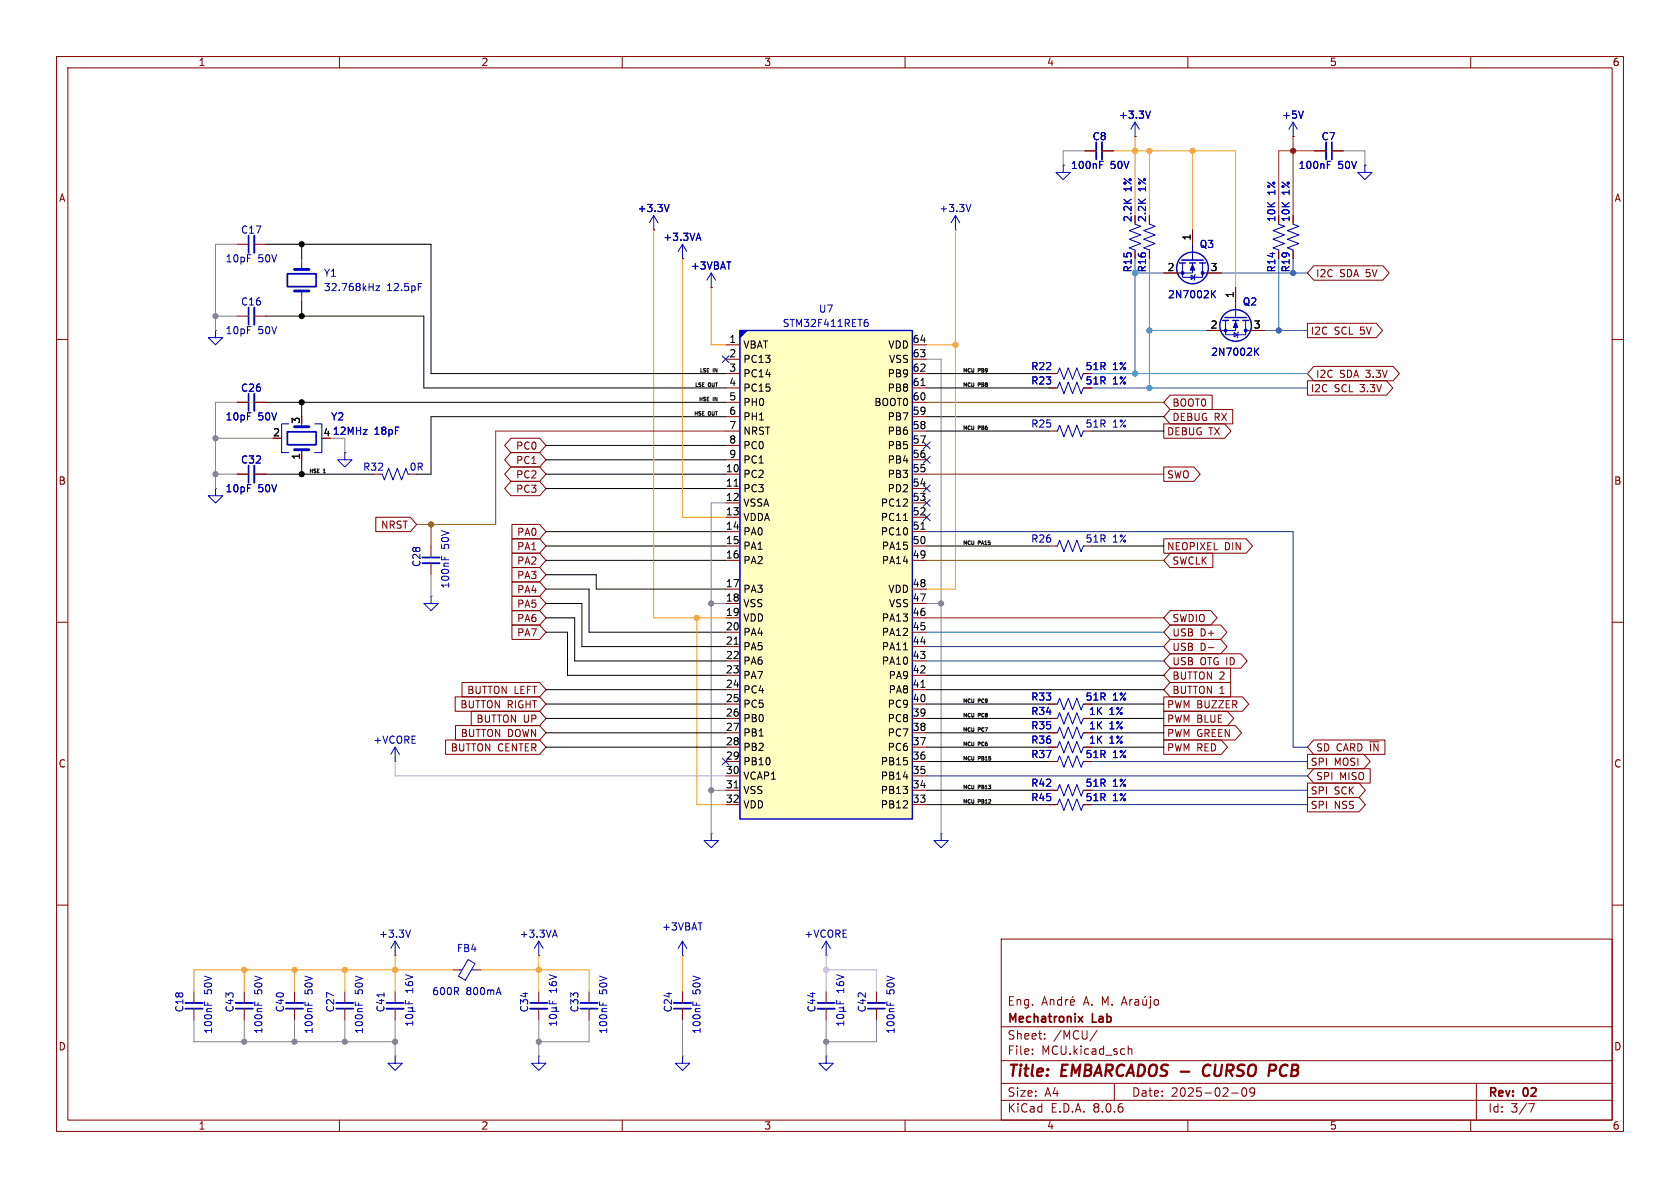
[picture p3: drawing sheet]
<svg xmlns="http://www.w3.org/2000/svg" width="297mm" height="210mm" viewBox="0 0 297 210" stroke-linecap="round" stroke-linejoin="round" font-family="sans-serif">
<defs><g id="words">
<g font-size="2.8" fill="#840000">
<text x="178" y="190.9">Title:</text>
<text x="187.7" y="190.9">EMBARCADOS -</text>
<text x="214.3" y="190.9">CURSO</text>
<text x="226.7" y="190.9">PCB</text>
</g>
<g font-size="2.1" fill="#840000">
<text x="178" y="178">Eng.</text>
<text x="191.6" y="178">A.</text>
<text x="178" y="184">Sheet:</text>
<text x="178" y="181.2">Mechatronix</text>
<text x="186.2" y="184">/MCU/</text>
<text x="193.2" y="181.2">Lab</text>
<text x="178" y="186.7">File:</text>
<text x="184.1" y="186.7">MCU.kicad_sch</text>
<text x="178" y="196.9">KiCad</text>
<text x="178" y="194.1">Size:</text>
<text x="184.7" y="194.1">A4</text>
<text x="185.7" y="196.9">E.D.A.</text>
<text x="193.3" y="196.9">8.0.6</text>
<text x="200" y="194.1">Date:</text>
<text x="207" y="194.1">2025-02-09</text>
<text x="263" y="194.3">Rev:</text>
<text x="263" y="196.9">Id:</text>
<text x="267.1" y="196.9">3/7</text>
<text x="269.4" y="194.3">02</text>
</g>
<g font-size="1.8" fill="#840000">
<text x="35" y="11.9">1</text>
<text x="85" y="11.9">2</text>
<text x="135" y="11.9">3</text>
<text x="185" y="11.9">4</text>
<text x="235" y="11.9">5</text>
<text x="285" y="11.9">6</text>
<text x="10.3" y="35.9">A</text>
<text x="285.3" y="35.9">A</text>
<text x="200.3" y="39.4" transform="rotate(-90 200.3 39.4)">2.2K</text>
<text x="202.8" y="39.4" transform="rotate(-90 202.8 39.4)">2.2K</text>
<text x="225.7" y="39.4" transform="rotate(-90 225.7 39.4)">10K</text>
<text x="228.2" y="39.4" transform="rotate(-90 228.2 39.4)">10K</text>
<text x="225.7" y="48.3" transform="rotate(-90 225.7 48.3)">R14</text>
<text x="232.6" y="49.2">I2C</text>
<text x="236.8" y="49.2">SDA 5V</text>
<text x="231.6" y="59.4">I2C</text>
<text x="235.9" y="59.4">SCL 5V</text>
<text x="191.8" y="65.6">51R</text>
<text x="191.8" y="68.2">51R</text>
<text x="231.6" y="69.5">I2C</text>
<text x="232.6" y="67">I2C</text>
<text x="235.9" y="69.5">SCL 3.3V</text>
<text x="236.8" y="67">SDA 3.3V</text>
<text x="206.2" y="77.2">DEBUG TX</text>
<text x="207.2" y="72.1">BOOT0</text>
<text x="207.2" y="74.6">DEBUG RX</text>
<text x="91.1" y="79.7">PC0</text>
<text x="91.1" y="82.2">PC1</text>
<text x="10.3" y="85.9">B</text>
<text x="91.1" y="84.8">PC2</text>
<text x="91.1" y="87.3">PC3</text>
<text x="206.2" y="84.8">SWO</text>
<text x="285.3" y="85.9">B</text>
<text x="67.3" y="93.7">NRST</text>
<text x="91.3" y="94.9">PA0</text>
<text x="91.3" y="100">PA2</text>
<text x="91.3" y="97.5">PA1</text>
<text x="206.2" y="97.5">NEOPIXEL</text>
<text x="207.2" y="100">SWCLK</text>
<text x="216.5" y="97.5">DIN</text>
<text x="91.3" y="107.6">PA5</text>
<text x="91.3" y="105.1">PA4</text>
<text x="91.3" y="102.6">PA3</text>
<text x="91.3" y="110.2">PA6</text>
<text x="91.3" y="112.7">PA7</text>
<text x="207.2" y="112.7">USB</text>
<text x="207.2" y="110.2">SWDIO</text>
<text x="212.1" y="112.7">D+</text>
<text x="207.2" y="115.3">USB</text>
<text x="207.2" y="117.8">USB</text>
<text x="212.1" y="115.3">D-</text>
<text x="212.1" y="117.8">OTG ID</text>
<text x="81.3" y="125.4">BUTTON RIGHT</text>
<text x="82.5" y="122.9">BUTTON LEFT</text>
<text x="191.8" y="124.1">51R</text>
<text x="206.2" y="125.4">PWM BUZZER</text>
<text x="207.2" y="122.9">BUTTON 1</text>
<text x="207.2" y="120.3">BUTTON 2</text>
<text x="81.3" y="130.5">BUTTON DOWN</text>
<text x="84.1" y="128">BUTTON UP</text>
<text x="206.2" y="130.5">PWM GREEN</text>
<text x="206.2" y="128">PWM BLUE</text>
<text x="10.3" y="135.9">C</text>
<text x="79.6" y="133">BUTTON CENTER</text>
<text x="191.8" y="134.2">51R</text>
<text x="206.2" y="133">PWM RED</text>
<text x="231.6" y="135.6">SPI</text>
<text x="232.6" y="133">SD CARD ~{IN}</text>
<text x="235.9" y="135.6">MOSI</text>
<text x="285.3" y="135.9">C</text>
<text x="191.8" y="139.3">51R</text>
<text x="191.8" y="141.8">51R</text>
<text x="231.6" y="140.7">SPI</text>
<text x="231.6" y="143.2">SPI</text>
<text x="232.6" y="138.1">SPI</text>
<text x="235.9" y="140.7">SCK</text>
<text x="235.9" y="143.2">NSS</text>
<text x="236.8" y="138.1">MISO</text>
<text x="10.3" y="185.9">D</text>
<text x="285.3" y="185.9">D</text>
<text x="35" y="199.9">1</text>
<text x="85" y="199.9">2</text>
<text x="135" y="199.9">3</text>
<text x="185" y="199.9">4</text>
<text x="235" y="199.9">5</text>
<text x="285" y="199.9">6</text>
</g>
<g font-size="1.8" fill="#0000c2">
<text x="197.7" y="21.2">+3.3V</text>
<text x="226.6" y="21.2">+5V</text>
<text x="193" y="25">C8</text>
<text x="233.5" y="25">C7</text>
<text x="189.2" y="30.1">100nF</text>
<text x="196.3" y="30.1">50V</text>
<text x="200.3" y="33.9" transform="rotate(-90 200.3 33.9)">1%</text>
<text x="202.8" y="33.9" transform="rotate(-90 202.8 33.9)">1%</text>
<text x="225.7" y="34.5" transform="rotate(-90 225.7 34.5)">1%</text>
<text x="228.2" y="34.5" transform="rotate(-90 228.2 34.5)">1%</text>
<text x="229.5" y="30.1">100nF</text>
<text x="236.5" y="30.1">50V</text>
<text x="42.5" y="41.5">C17</text>
<text x="112.6" y="37.7">+3.3V</text>
<text x="166" y="37.7">+3.3V</text>
<text x="39.8" y="46.6">10pF</text>
<text x="45.6" y="46.6">50V</text>
<text x="117.2" y="42.8">+3.3VA</text>
<text x="122" y="47.9">+3VBAT</text>
<text x="212" y="44">Q3</text>
<text x="57.2" y="49.1">Y1</text>
<text x="57.2" y="51.7">32.768kHz</text>
<text x="68.4" y="51.7">12.5pF</text>
<text x="200.3" y="48.3" transform="rotate(-90 200.3 48.3)">R15</text>
<text x="202.8" y="48.3" transform="rotate(-90 202.8 48.3)">R16</text>
<text x="206.4" y="52.9">2N7002K</text>
<text x="228.2" y="48.3" transform="rotate(-90 228.2 48.3)">R19</text>
<text x="39.8" y="59.3">10pF</text>
<text x="42.5" y="54.2">C16</text>
<text x="45.6" y="59.3">50V</text>
<text x="138.3" y="58">STM32F411RET6</text>
<text x="144.7" y="55.5">U7</text>
<text x="219.6" y="54.2">Q2</text>
<text x="182.2" y="65.6">R22</text>
<text x="196.7" y="65.6">1%</text>
<text x="214" y="63.1">2N7002K</text>
<text x="42.5" y="69.4">C26</text>
<text x="182.2" y="68.2">R23</text>
<text x="196.7" y="68.2">1%</text>
<text x="39.8" y="74.5">10pF</text>
<text x="45.6" y="74.5">50V</text>
<text x="58.4" y="74.5">Y2</text>
<text x="58.7" y="77.1">12MHz</text>
<text x="66.1" y="77.1">18pF</text>
<text x="182.2" y="75.8">R25</text>
<text x="191.8" y="75.8">51R</text>
<text x="196.7" y="75.8">1%</text>
<text x="42.5" y="82.1">C32</text>
<text x="64.1" y="83.4">R32</text>
<text x="72.3" y="83.4">0R</text>
<text x="39.8" y="87.2">10pF</text>
<text x="45.6" y="87.2">50V</text>
<text x="74.5" y="100.3" transform="rotate(-90 74.5 100.3)">C28</text>
<text x="79.6" y="97.1" transform="rotate(-90 79.6 97.1)">50V</text>
<text x="182.2" y="96.1">R26</text>
<text x="191.8" y="96.1">51R</text>
<text x="196.7" y="96.1">1%</text>
<text x="79.6" y="104.1" transform="rotate(-90 79.6 104.1)">100nF</text>
<text x="182.2" y="124.1">R33</text>
<text x="196.7" y="124.1">1%</text>
<text x="65.9" y="131.7">+VCORE</text>
<text x="182.2" y="131.7">R36</text>
<text x="182.2" y="129.1">R35</text>
<text x="182.2" y="126.6">R34</text>
<text x="192.4" y="131.7">1K</text>
<text x="192.4" y="129.1">1K</text>
<text x="192.4" y="126.6">1K</text>
<text x="196.1" y="131.7">1%</text>
<text x="196.1" y="129.1">1%</text>
<text x="196.1" y="126.6">1%</text>
<text x="182.2" y="134.2">R37</text>
<text x="196.7" y="134.2">1%</text>
<text x="182.2" y="139.3">R42</text>
<text x="182.2" y="141.8">R45</text>
<text x="196.7" y="139.3">1%</text>
<text x="196.7" y="141.8">1%</text>
<text x="66.9" y="166">+3.3V</text>
<text x="91.8" y="166">+3.3VA</text>
<text x="116.9" y="164.7">+3VBAT</text>
<text x="142.1" y="166">+VCORE</text>
<text x="80.7" y="168.5">FB4</text>
<text x="32.6" y="179.1" transform="rotate(-90 32.6 179.1)">C18</text>
<text x="37.7" y="175.8" transform="rotate(-90 37.7 175.8)">50V</text>
<text x="41.5" y="179.1" transform="rotate(-90 41.5 179.1)">C43</text>
<text x="46.6" y="175.8" transform="rotate(-90 46.6 175.8)">50V</text>
<text x="50.4" y="179.1" transform="rotate(-90 50.4 179.1)">C40</text>
<text x="55.5" y="175.8" transform="rotate(-90 55.5 175.8)">50V</text>
<text x="59.3" y="179.1" transform="rotate(-90 59.3 179.1)">C27</text>
<text x="64.4" y="175.8" transform="rotate(-90 64.4 175.8)">50V</text>
<text x="68.2" y="179.1" transform="rotate(-90 68.2 179.1)">C41</text>
<text x="73.3" y="175.6" transform="rotate(-90 73.3 175.6)">16V</text>
<text x="76.3" y="176.1">600R</text>
<text x="82.4" y="176.1">800mA</text>
<text x="93.6" y="179.1" transform="rotate(-90 93.6 179.1)">C34</text>
<text x="98.7" y="175.6" transform="rotate(-90 98.7 175.6)">16V</text>
<text x="102.5" y="179.1" transform="rotate(-90 102.5 179.1)">C33</text>
<text x="107.5" y="175.8" transform="rotate(-90 107.5 175.8)">50V</text>
<text x="119" y="179.1" transform="rotate(-90 119 179.1)">C24</text>
<text x="124.1" y="175.8" transform="rotate(-90 124.1 175.8)">50V</text>
<text x="144.4" y="179.1" transform="rotate(-90 144.4 179.1)">C44</text>
<text x="149.5" y="175.6" transform="rotate(-90 149.5 175.6)">16V</text>
<text x="153.3" y="179.1" transform="rotate(-90 153.3 179.1)">C42</text>
<text x="158.3" y="175.8" transform="rotate(-90 158.3 175.8)">50V</text>
<text x="37.7" y="182.9" transform="rotate(-90 37.7 182.9)">100nF</text>
<text x="46.6" y="182.9" transform="rotate(-90 46.6 182.9)">100nF</text>
<text x="55.5" y="182.9" transform="rotate(-90 55.5 182.9)">100nF</text>
<text x="64.4" y="182.9" transform="rotate(-90 64.4 182.9)">100nF</text>
<text x="107.5" y="182.9" transform="rotate(-90 107.5 182.9)">100nF</text>
<text x="124.1" y="182.9" transform="rotate(-90 124.1 182.9)">100nF</text>
<text x="158.3" y="182.9" transform="rotate(-90 158.3 182.9)">100nF</text>
</g>
<g font-size="1.8">
<text x="210.6" y="42.6" transform="rotate(-90 210.6 42.6)">1</text>
<text x="206.3" y="48">2</text>
<text x="213.9" y="48">3</text>
<text x="218.2" y="52.8" transform="rotate(-90 218.2 52.8)">1</text>
<text x="213.9" y="58.2">2</text>
<text x="221.5" y="58.2">3</text>
<text x="128.8" y="60.7">1</text>
<text x="128.8" y="63.2">2</text>
<text x="128.8" y="65.8">3</text>
<text x="131.3" y="61.8">VBAT</text>
<text x="131.3" y="64.4">PC13</text>
<text x="157" y="61.8">VDD</text>
<text x="157.1" y="64.4">VSS</text>
<text x="161.2" y="65.8">62</text>
<text x="161.2" y="63.2">63</text>
<text x="161.2" y="60.7">64</text>
<text x="128.8" y="68.3">4</text>
<text x="128.8" y="70.9">5</text>
<text x="131.3" y="66.9">PC14</text>
<text x="131.3" y="69.4">PC15</text>
<text x="131.3" y="72">PH0</text>
<text x="154.5" y="72">BOOT0</text>
<text x="156.8" y="69.4">PB8</text>
<text x="156.8" y="66.9">PB9</text>
<text x="161.2" y="70.9">60</text>
<text x="161.2" y="68.3">61</text>
<text x="48.2" y="77.2">2</text>
<text x="53.1" y="75" transform="rotate(-90 53.1 75)">3</text>
<text x="57.1" y="77.2">4</text>
<text x="128.8" y="73.4">6</text>
<text x="128.8" y="75.9">7</text>
<text x="131.3" y="74.5">PH1</text>
<text x="131.3" y="77.1">NRST</text>
<text x="156.8" y="77.1">PB6</text>
<text x="156.8" y="74.5">PB7</text>
<text x="161.2" y="75.9">58</text>
<text x="161.2" y="73.4">59</text>
<text x="53.1" y="81.4" transform="rotate(-90 53.1 81.4)">1</text>
<text x="128.2" y="83.6">10</text>
<text x="128.8" y="78.5">8</text>
<text x="128.8" y="81">9</text>
<text x="131.3" y="79.6">PC0</text>
<text x="131.3" y="82.1">PC1</text>
<text x="156.8" y="82.1">PB4</text>
<text x="156.8" y="79.6">PB5</text>
<text x="161.2" y="83.6">55</text>
<text x="161.2" y="81">56</text>
<text x="161.2" y="78.5">57</text>
<text x="128.2" y="86.1">11</text>
<text x="128.2" y="88.6">12</text>
<text x="131.3" y="84.7">PC2</text>
<text x="131.3" y="87.2">PC3</text>
<text x="131.3" y="89.8">VSSA</text>
<text x="155.6" y="89.8">PC12</text>
<text x="156.8" y="87.2">PD2</text>
<text x="156.8" y="84.7">PB3</text>
<text x="161.2" y="88.6">53</text>
<text x="161.2" y="86.1">54</text>
<text x="128.2" y="91.2">13</text>
<text x="128.2" y="93.7">14</text>
<text x="131.3" y="92.3">VDDA</text>
<text x="131.3" y="94.8">PA0</text>
<text x="155.6" y="94.8">PC10</text>
<text x="155.6" y="92.3">PC11</text>
<text x="161.2" y="93.7">51</text>
<text x="161.2" y="91.2">52</text>
<text x="128.2" y="96.3">15</text>
<text x="128.2" y="98.8">16</text>
<text x="131.3" y="97.4">PA1</text>
<text x="131.3" y="99.9">PA2</text>
<text x="155.8" y="99.9">PA14</text>
<text x="155.8" y="97.4">PA15</text>
<text x="161.2" y="98.8">49</text>
<text x="161.2" y="96.3">50</text>
<text x="128.2" y="103.9">17</text>
<text x="128.2" y="106.4">18</text>
<text x="131.3" y="105">PA3</text>
<text x="131.3" y="107.5">VSS</text>
<text x="157" y="105">VDD</text>
<text x="157.1" y="107.5">VSS</text>
<text x="161.2" y="106.4">47</text>
<text x="161.2" y="103.9">48</text>
<text x="128.2" y="109">19</text>
<text x="128.2" y="111.5">20</text>
<text x="131.3" y="110.1">VDD</text>
<text x="131.3" y="112.6">PA4</text>
<text x="155.8" y="112.6">PA12</text>
<text x="155.8" y="110.1">PA13</text>
<text x="161.2" y="111.5">45</text>
<text x="161.2" y="109">46</text>
<text x="128.2" y="114">21</text>
<text x="128.2" y="116.6">22</text>
<text x="128.2" y="119.1">23</text>
<text x="131.3" y="115.2">PA5</text>
<text x="131.3" y="117.7">PA6</text>
<text x="155.8" y="117.7">PA10</text>
<text x="155.8" y="115.2">PA11</text>
<text x="161.2" y="119.1">42</text>
<text x="161.2" y="116.6">43</text>
<text x="161.2" y="114">44</text>
<text x="128.2" y="121.7">24</text>
<text x="128.2" y="124.2">25</text>
<text x="131.3" y="120.2">PA7</text>
<text x="131.3" y="122.8">PC4</text>
<text x="131.3" y="125.3">PC5</text>
<text x="156.8" y="125.3">PC9</text>
<text x="157" y="122.8">PA8</text>
<text x="157" y="120.2">PA9</text>
<text x="161.2" y="124.2">40</text>
<text x="161.2" y="121.7">41</text>
<text x="128.2" y="126.7">26</text>
<text x="128.2" y="129.3">27</text>
<text x="128.2" y="131.8">28</text>
<text x="131.3" y="127.9">PB0</text>
<text x="131.3" y="130.4">PB1</text>
<text x="156.8" y="130.4">PC7</text>
<text x="156.8" y="127.9">PC8</text>
<text x="161.2" y="131.8">37</text>
<text x="161.2" y="129.3">38</text>
<text x="161.2" y="126.7">39</text>
<text x="128.2" y="134.4">29</text>
<text x="128.2" y="136.9">30</text>
<text x="131.3" y="132.9">PB2</text>
<text x="131.3" y="135.5">PB10</text>
<text x="155.6" y="135.5">PB15</text>
<text x="156.8" y="132.9">PC6</text>
<text x="161.2" y="136.9">35</text>
<text x="161.2" y="134.4">36</text>
<text x="128.2" y="139.4">31</text>
<text x="128.2" y="142">32</text>
<text x="131.3" y="138">VCAP1</text>
<text x="131.3" y="140.6">VSS</text>
<text x="131.3" y="143.1">VDD</text>
<text x="155.6" y="143.1">PB12</text>
<text x="155.6" y="140.6">PB13</text>
<text x="155.6" y="138">PB14</text>
<text x="161.2" y="142">33</text>
<text x="161.2" y="139.4">34</text>
</g>
<g font-size=".9" fill="#0f0f0f">
<text x="123.5" y="65.9">LSE</text>
<text x="126" y="65.9">IN</text>
<text x="170.2" y="65.9">MCU</text>
<text x="173" y="65.9">PB9</text>
<text x="122.7" y="68.4">LSE</text>
<text x="123.4" y="70.9">HSE</text>
<text x="125.2" y="68.4">OUT</text>
<text x="126" y="70.9">IN</text>
<text x="170.2" y="68.4">MCU</text>
<text x="173" y="68.4">PB8</text>
<text x="122.5" y="73.5">HSE</text>
<text x="125.2" y="73.5">OUT</text>
<text x="170.2" y="76">MCU</text>
<text x="173" y="76">PB6</text>
<text x="54.6" y="83.6">HSE</text>
<text x="57.3" y="83.6">1</text>
<text x="170.2" y="96.3">MCU</text>
<text x="173" y="96.3">PA15</text>
<text x="170.2" y="124.3">MCU</text>
<text x="173" y="124.3">PC9</text>
<text x="170.2" y="131.9">MCU</text>
<text x="170.2" y="126.8">MCU</text>
<text x="170.2" y="129.4">MCU</text>
<text x="173" y="131.9">PC6</text>
<text x="173" y="126.8">PC8</text>
<text x="173" y="129.4">PC7</text>
<text x="170.2" y="134.4">MCU</text>
<text x="173" y="134.4">PB15</text>
<text x="170.2" y="139.5">MCU</text>
<text x="170.2" y="142.1">MCU</text>
<text x="173" y="139.5">PB13</text>
<text x="173" y="142.1">PB12</text>
</g>
</g></defs>
<g fill="none" stroke="#840000" stroke-width=".18">
<path d="M10 10h277v190h-277zM12 12h273v186h-273zM60 10v2M110 10v2M160 10v2M210 10v2M260 10v2M10 60h2M38.1 58.4h.1M125.7 50.8h.1M285 60h2M10 110h2"/>
<path d="M76.2 105.4h.1M285 110h2M185.4 132.1h1.3M191.8 132.1h1.2M10 160h2M285 160h2M52.1 175.3v2M52.1 178.3v2M61 175.3v2M61 178.3v2M177 166h108v32h-108zM184.2 177.7l.5-1.5 .5 1.5"/>
<path d="M184.3 177.3h.7M185.7 176.7v1M185.7 176.8l.2-.1 .3 .1 .1 .9M187.7 176.8l-.5-.1-.2 .3v.4l.1 .2h.6M187.7 176.2v1.5M188.4 176.7v1M188.8 176.7l-.3 .1-.1 .2M189.2 177.2l.8-.1-.1-.3-.4-.1-.3 .2 .1 .7h.6M189.7 176.1l-.2 .2M194.9 177.7v-1.5l.5 1.1 .5-1.1v1.5M196.6 177.6v.1M198.2 177.7l.5-1.5 .5 1.5"/>
<path d="M198.4 177.3h.7M199.7 176.7v1M200.2 176.7l-.3 .1-.2 .2M200.7 176.8h.5l.1 .9M201.3 177.1h-.5a.29 .29 0 0 0-.2 .3 .29 .29 0 0 0 .2 .3l.5-.1M202 176.7l.1 .9 .4 .1 .2-.1M202.5 176.1l-.2 .2M202.7 176.7v1M203.4 176.2v.1M203.4 176.7v1.3l-.3 .2M204.2 176.8l.3-.1 .3 .3v.4l-.3 .3-.3-.1-.2-.2v-.4zM60 198v2"/>
<path d="M110 198v2M160 198v2M177 194.5h108M177 191.5h108M177 187.5h108M177 181.5h108M182.5 186.3v.1M182.5 185.5v.1M184.7 183.6v.1M184.7 182.8v.1M194 182.1l-1.3 2M197 191.5v3"/>
<path d="M199.5 184.9v1.5M199.5 185.5l.2-.1 .3 .1 .1 .9M210 198v2M217.7 193.2h1.2M219.7 192.4l.2-.1a.81 .81 0 0 1 .6 .6 .81 .81 0 0 1-.3 .8l-.2 .1a.81 .81 0 0 1-.3-1.4zM221.8 192.9l-.3 .3h-.3l-.2-.3 .1-.5 .4-.1 .2 .1a.99 .99 0 0 1-.3 1.4h-.3M260 198v2M261 191.5v6.5M270.2 195.1h1l-.6 1.5"/>
</g>
<path d="M213.6 188.2a1.13 1.13 0 0 0-.9 .7 1.13 1.13 0 0 0 .2 1.2l.3 .1 .5-.1M225.4 188.3a.53 .53 0 0 1 0 .8" fill="none" stroke="#840000" stroke-width=".4"/>
<path d="M190.6 179.7l.8 1M191.4 179.7l-.8 1" fill="none" stroke="#840000" stroke-width=".3"/>
<path d="M38.1 58.4v1.3h1.3l-1.3 1.3-1.3-1.3h1.3M125.7 48.3l-.7 1.2M125.7 48.3v2.5M125.7 48.3l.8 1.2M76.2 105.4v1.3h1.3l-1.3 1.3-1.3-1.3h1.3M186.7 132.1h.2l.4-1 .8 2 .7-2 .8 2 .8-2 .7 2 .4-1h.3M53.9 177.1v.6M54.5 177.3v.4M62.8 177.1v.6M63.4 177.3v.4" fill="none" stroke="#0000c2" stroke-width=".18"/>
<path d="M50.5 177.3h3.1M59.4 177.3h3.1" fill="none" stroke="#0000c2" stroke-width=".33"/>
<path d="M50.5 178.3h3.1M59.4 178.3h3.1" fill="none" stroke="#0000c2" stroke-width=".3"/>
<path d="M130.8 58.4h30.5v86.4h-30.5z" fill="#ffffc2"/>
<g fill="none" stroke="#0000c2" stroke-width=".25">
<path d="M130.8 58.4h30.5v86.4h-30.5zM208.5 46.5h1M208.9 46h3.8M210.3 46.5h1M212.1 46.5h1M216.2 56.6h1M216.5 56.1h3.8M217.9 56.6h1M219.7 56.6h1"/>
<circle cx="210.8" cy="47.4" r="2.79"/>
<circle cx="218.4" cy="57.5" r="2.79"/>
</g>
<g fill="#0000c2" stroke="#0000c2" stroke-width=".18">
<path d="M130.8 58.4h1.3l-1.3 1.3z"/>
<path d="M218.4 56.9l.4 1h-.7z"/>
<path d="M210.8 46.7l.4 1.1h-.8z"/>
<circle cx="216.7" cy="58.4" r=".25"/>
<circle cx="220.2" cy="58.4" r=".25"/>
<circle cx="209" cy="48.3" r=".25"/>
<circle cx="212.6" cy="48.3" r=".25"/>
</g>
<g fill="none" stroke="#840000" stroke-width=".18">
<path d="M188 29.2h.1M191.8 26.7h2M194.8 26.7h2M200.7 24.1h.1M228.6 24.1h.1M232.4 26.7h2M235.5 26.7h2M241.3 29.2h.1M41.9 55.9h2M41.9 43.2h2M45 55.9h2M45 43.2h2"/>
<path d="M53.3 45.7v1.3M53.3 52.1v1.2M115.6 40.6h.1M120.6 45.7h.1M125.7 50.8h.1M168.9 40.6h.1M200.7 44.5v1.2M203.2 44.5v1.2M205.7 48.3h2.6M210.8 40.6v2.6M213.4 58.4h2.5M213.4 48.3h2.5"/>
<path d="M218.4 50.8v2.5M221 58.4h2.5M228.6 44.5v1.2M231.1 57.1h12.2l1.1 1.3-1.1 1.3h-12.2zM232.3 47h12.2l1.1 1.3-1.1 1.2h-12.2l-1.2-1.2zM41.9 71.1h2M45 71.1h2M90.3 77.5h5.1l1.1 1.2-1.1 1.3h-5.1l-1.1-1.3zM128.3 61h2.5M128.3 63.5h2.5M128.3 66h2.5M128.3 68.6h2.5"/>
<path d="M128.3 71.1h2.5M128.3 78.7h2.5M128.3 76.2h2.5M128.3 73.7h2.5M161.3 61h2.5M161.3 63.5h2.5M161.3 66h2.5M161.3 68.6h2.5M161.3 71.1h2.5M161.3 78.7h2.5M161.3 76.2h2.5M161.3 73.7h2.5"/>
<path d="M185.4 66h1.3M185.4 68.6h1.3M185.4 76.2h1.3M205.7 74.9h10.8l1.1 1.3-1.1 1.3h-10.8zM206.9 69.8h7.4v2.6h-7.4l-1.2-1.3zM206.9 72.4h11v2.5h-11l-1.2-1.2zM231.1 67.3h14l1.1 1.3-1.1 1.3h-14zM232.3 64.8h14l1.1 1.2-1.1 1.3h-14l-1.2-1.3zM38.1 86.4h.1M41.9 83.8h2M45 83.8h2M53.3 80v1.3"/>
<path d="M61 80h.1M66.4 91.4h6.1l1.2 1.3-1.2 1.3h-6.1zM76.2 96.5v2.1M76.2 99.6v2M90.3 80h5.1l1.1 1.3-1.1 1.3h-5.1l-1.1-1.3zM90.3 82.5h5.1l1.1 1.3-1.1 1.3h-5.1l-1.1-1.3zM90.3 85.1h5.1l1.1 1.3-1.1 1.2h-5.1l-1.1-1.2zM90.5 97.8h4.9l1.1 1.3-1.1 1.2h-4.9zM90.5 92.7h4.9l1.1 1.3-1.1 1.3h-4.9zM90.5 95.2h4.9l1.1 1.3-1.1 1.3h-4.9zM128.3 83.8h2.5M128.3 86.4h2.5"/>
<path d="M128.3 88.9h2.5M128.3 91.4h2.5M128.3 94h2.5M128.3 96.5h2.5M128.3 99.1h2.5M128.3 81.3h2.5M161.3 83.8h2.5M161.3 86.4h2.5M161.3 88.9h2.5M161.3 91.4h2.5M161.3 94h2.5M161.3 96.5h2.5"/>
<path d="M161.3 99.1h2.5M161.3 81.3h2.5M185.4 96.5h1.3M205.7 95.2h14.6l1.1 1.3-1.1 1.3h-14.6zM205.7 82.5h5.4l1.1 1.3-1.1 1.3h-5.4zM206.9 97.8h7.5v2.5h-7.5l-1.2-1.2zM90.5 105.4h4.9l1.1 1.3-1.1 1.3h-4.9zM90.5 107.9h4.9l1.1 1.3-1.1 1.3h-4.9zM90.5 110.5h4.9l1.1 1.3-1.1 1.2h-4.9zM90.5 102.9h4.9l1.1 1.2-1.1 1.3h-4.9zM90.5 100.3h4.9l1.1 1.3-1.1 1.3h-4.9zM128.3 104.1h2.5"/>
<path d="M128.3 106.7h2.5M128.3 109.2h2.5M128.3 111.8h2.5M128.3 114.3h2.5M128.3 116.8h2.5M128.3 119.4h2.5M161.3 104.1h2.5M161.3 106.7h2.5M161.3 109.2h2.5M161.3 111.8h2.5M161.3 114.3h2.5M161.3 116.8h2.5"/>
<path d="M161.3 119.4h2.5M206.9 110.5h8.9l1.1 1.3-1.1 1.2h-8.9l-1.2-1.2zM206.9 107.9h7.2l1.1 1.3-1.1 1.3h-7.2l-1.2-1.3zM206.9 113h8.9l1.1 1.3-1.1 1.3h-8.9l-1.2-1.3zM206.9 118.1h10.7v2.6h-10.7l-1.2-1.3zM206.9 115.6h12.5l1.1 1.2-1.1 1.3h-12.5l-1.2-1.3zM213.6 114.5h1M69.8 134.6h.1M78.8 130.8h16.6l1.1 1.3-1.1 1.3h-16.6zM80.5 123.2h14.9l1.1 1.3-1.1 1.2h-14.9zM80.5 128.3h14.9l1.1 1.2-1.1 1.3h-14.9zM81.7 120.6h13.7l1.1 1.3-1.1 1.3h-13.7z"/>
<path d="M83.3 125.7h12.1l1.1 1.3-1.1 1.3h-12.1zM128.3 121.9h2.5M128.3 124.5h2.5M128.3 127h2.5M128.3 129.5h2.5M128.3 132.1h2.5M128.3 134.6h2.5M128.3 137.2h2.5M128.3 139.7h2.5M161.3 121.9h2.5M161.3 124.5h2.5M161.3 127h2.5"/>
<path d="M161.3 129.5h2.5M161.3 132.1h2.5M161.3 134.6h2.5M161.3 137.2h2.5M161.3 139.7h2.5M185.4 124.5h1.3M185.4 127h1.3M185.4 129.5h1.3M185.4 132.1h1.3M185.4 134.6h1.3M185.4 139.7h1.3M191.8 127h1.2"/>
<path d="M191.8 129.5h1.2M191.8 132.1h1.2M205.7 130.8h10.2l1.1 1.3-1.1 1.3h-10.2zM205.7 123.2h14l1.1 1.3-1.1 1.2h-14zM205.7 128.3h12.7l1.1 1.2-1.1 1.3h-12.7zM205.7 125.7h11.3l1.1 1.3-1.1 1.3h-11.3zM206.9 120.6h10.7v2.6h-10.7l-1.2-1.3zM231.1 133.3h10l1.1 1.3-1.1 1.3h-10zM231.1 138.4h9.2l1.1 1.3-1.1 1.3h-9.2zM232.3 135.9h9.9v2.5h-9.9l-1.2-1.2zM232.3 130.8h12.5v2.6h-12.5l-1.2-1.3zM125.7 147.3h.1"/>
<path d="M128.3 142.2h2.5M161.3 142.2h2.5M166.4 147.3h.1M185.4 142.2h1.3M231.1 141h9.2l1.1 1.2-1.1 1.3h-9.2zM34.3 175.3v2M34.3 178.3v2M43.2 175.3v2M43.2 178.3v2M69.8 168.9h.1M69.8 175.3v2M69.8 178.3v2"/>
<path d="M80 171.5h1.3M83.8 171.5h1.3M95.2 168.9h.1M95.2 175.3v2M95.2 178.3v2M104.1 175.3v2M104.1 178.3v2M120.6 168.9h.1M120.6 175.3v2M120.6 178.3v2M146 168.9h.1M146 175.3v2"/>
<path d="M146 178.3v2M154.9 175.3v2M154.9 178.3v2M69.8 186.7h.1M95.2 186.7h.1M120.6 186.7h.1M146 186.7h.1"/>
</g>
<g fill="none" stroke="#000" stroke-width=".18">
<path d="M47 43.2h29.2v22.8h52.1M47 55.9h27.9v12.7h53.4M53.3 43.2v2.5M53.3 53.3v2.6M47 71.1h81.3M53.3 71.1v2.6M96.5 78.7h31.8M128.3 73.7h-52.1v10.1h-2.5M162.8 68.2h.7M163.8 73.7h41.9M163.8 66h21.6M163.8 68.6h21.6"/>
<path d="M163.8 76.2h21.6M193 76.2h12.7M47 83.8h19M53.3 81.3v2.5M96.5 99.1h31.8M96.5 96.5h31.8M96.5 94h31.8M96.5 81.3h31.8M96.5 86.4h31.8M96.5 83.8h31.8M129.8 85.9h.7M159.7 92h.7"/>
<path d="M162.8 93.6h.7M163.8 96.5h21.6M193 96.5h12.7M96.5 101.6h8.9v2.5h22.9M96.5 104.1h7.6v7.7h24.2M96.5 111.8h3.8v7.6h28M96.5 109.2h5.1v7.6h26.7M96.5 106.7h6.4v7.6h25.4M129.8 113.9h.7M159.7 114.9h.7M163.8 119.4h41.9M96.5 129.5h31.8"/>
<path d="M96.5 127h31.8M96.5 121.9h31.8M96.5 124.5h31.8M96.5 132.1h31.8M129.8 139.3h.7M162.8 121.5h.7M163.8 129.5h21.6M163.8 127h21.6M163.8 121.9h41.9M163.8 124.5h21.6M163.8 132.1h21.6M163.8 134.6h21.6"/>
<path d="M163.8 139.7h21.6M193 129.5h12.7M193 127h12.7M193 124.5h12.7M193 132.1h12.7M163.8 142.2h21.6"/>
</g>
<g fill="none" stroke="#0000c2" stroke-width=".18">
<path d="M203.4 19.6l-.4 1.3M230.4 19.6l-.4 1.3M115.6 38.1l-.8 1.3M115.6 38.1v2.5M115.6 38.1l.7 1.3M118.3 36.1l-.4 1.3M168.9 38.1l-.8 1.3M168.9 38.1v2.5M168.9 38.1l.8 1.3M171.6 36.1l-.4 1.3M188 29.2v1.3h1.2l-1.2 1.3-1.3-1.3h1.3M194.4 29.1h.4"/>
<path d="M194.4 28.5h.6M200.7 39.6l1 .4-2.1 .8 2.1 .7-2.1 .8 2.1 .8-2.1 .7 1.1 .4v.3M200.7 21.6l-.8 1.3M200.7 21.6v2.5M200.7 21.6l.7 1.3M203.2 39.6l1 .4-2 .8 2 .7-2 .8 2 .8-2 .7 1 .4v.3M226.1 39.6l1 .4-2.1 .8 2.1 .7-2.1 .8 2.1 .8-2.1 .7 1.1 .4v.3M228.6 39.6l1 .4-2 .8 2 .7-2 .8 2 .8-2 .7 1 .4v.3M228.6 21.6l-.8 1.3M228.6 21.6v2.5M228.6 21.6l.8 1.3M234.7 29.1h.4"/>
<path d="M234.7 28.5h.6M241.3 29.2v1.3h1.3l-1.3 1.3-1.3-1.3h1.3M53.3 47v.6M53.3 51.4v.7M66.5 50.5h.6l-.6 .9h.6M74 50.1h.6M120.6 43.2l-.7 1.3M120.6 43.2v2.5M120.6 43.2l.8 1.3M123.2 42.1h.6M123.5 41.2l.4 1.3M153 56.9l.4 .1 .1 .2-.1 .4-.4 .1"/>
<path d="M153.4 56.5h-.4M209 46.5v2.5h3.6v-2.5M210.6 48.6l.6 .4-.6 .4zM210.8 46.5v1.8h-2.5M210.8 43.2v2.8M211.3 48.5l-.1 .1v.8l-.1 .1M212.6 48.3h.8M214.4 51.9l.5 .7M214.9 51.4l-.7 .7M216.7 56.6v2.6h3.5v-2.6M218.2 58.8l.6 .4-.6 .4zM218.4 56.6v1.8h-2.5"/>
<path d="M218.4 53.3v2.8M218.9 58.7l-.1 .1v.8l-.1 .1M220.2 58.4h.8M49.5 77.5h.3M51.1 74.9h-1.3v5.1h1.3M53.3 79.5v.5M55.6 74.9h1.3v5.1h-1.3M186.7 66h.2l.4-1 .8 2.1 .7-2.1 .8 2.1 .8-2.1 .7 2.1 .4-1.1M186.7 76.2h.2l.4-1 .8 2 .7-2 .8 2 .8-2 .7 2 .4-1M186.7 68.6h.2l.4-1 .8 2 .7-2 .8 2 .8-2 .7 2 .4-1M222 62.1l.5 .7M222.5 61.5l-.7 .8"/>
<path d="M38.1 86.4v1.2h1.3l-1.3 1.3-1.3-1.3h1.3M61 80v1.3h1.2l-1.2 1.3-1.3-1.3h1.3M67.6 83.8l.3 1 .8-2 .8 2 .7-2 .8 2 .8-2 .3 1M78 98.3v.6M78.7 98.5v.4M186.7 96.5h.2l.4-1 .8 2 .7-2 .8 2 .8-2 .7 2 .4-1M69.8 132.1v2.5M69.8 132.1l-.7 1.3M69.8 132.1l.8 1.3M186.7 129.5h.2l.4-1 .8 2.1 .7-2.1 .8 2.1 .8-2.1 .7 2.1 .4-1.1h.3M186.7 127h.2l.4-1 .8 2 .7-2 .8 2 .8-2 .7 2 .4-1h.3M186.7 134.6h.2l.4-1 .8 2 .7-2 .8 2 .8-2 .7 2 .4-1"/>
<path d="M186.7 139.7h.2l.4-1 .8 2 .7-2 .8 2 .8-2 .7 2 .4-1M186.7 124.5h.2l.4-1.1 .8 2.1 .7-2.1 .8 2.1 .8-2.1 .7 2.1 .4-1M125.7 147.3v1.3h1.3l-1.3 1.3-1.2-1.3h1.2M166.4 147.3v1.3h1.2l-1.2 1.3-1.3-1.3h1.3M186.7 142.2h.2l.4-1 .8 2.1 .7-2.1 .8 2.1 .8-2.1 .7 2.1 .4-1.1M36.1 177.1v.6M36.7 177.3v.4M45 177.1v.6M45.6 177.3v.4M67.9 175.5v.7M69.8 166.4l-.7 1.2M69.8 166.4v2.5"/>
<path d="M69.8 166.4l.8 1.2M71.7 176.8v.6h1.3M71.8 179.5a.75 .75 0 0 1 1.2 .2 .72 .72 0 0 1-1.3-.1zM72.1 178.8h1.3M72.1 178.2h.7M72.3 177v.4M72.6 164.4l-.5 1.3M72.8 178.2l.2 .2v.2l-.2 .2M73 178l-.2 .2M81.3 171.5h.4M82.8 169.6l1.2 .7-1.7 3-1.2-.7zM83.3 171.5h.5"/>
<path d="M95.2 166.4l-.7 1.2M95.2 166.4v2.5M95.2 166.4l.8 1.2M97.1 176.8v.6h1.3M97.2 179.5a.75 .75 0 0 1 1.2 .2 .72 .72 0 0 1-1.3-.1zM97.5 178.8h1.3M97.5 178.2h.7M97.7 177v.4M97.8 165.3h.6M98.1 164.4l.4 1.3M98.2 178.2l.2 .2v.2l-.2 .2M98.4 178l-.2 .2"/>
<path d="M106 177.1v.6M106.6 177.3v.4M120.6 166.4v2.5M120.6 166.4l-.7 1.2M120.6 166.4l.8 1.2M122.5 177.1v.6M123.1 177.3v.4M146 166.4l-.7 1.2M146 166.4v2.5M146 166.4l.8 1.2M147.9 176.8v.6h1.3M148 179.5a.75 .75 0 0 1 1.2 .2 .72 .72 0 0 1-1.3-.1z"/>
<path d="M148.3 178.8h1.3M148.3 178.2h.7M148.5 177v.4M149 178.2l.2 .2v.2l-.2 .2M149.2 178l-.2 .2M156.8 177.1v.6M157.4 177.3v.4M69.8 186.7v1.3h1.3l-1.3 1.2-1.2-1.2h1.2M73 180.5v.8M73 180.9h-1.3l.4 .4M95.2 186.7v1.3h1.3l-1.3 1.2-1.2-1.2h1.2M98.4 180.9h-1.3l.4 .4"/>
<path d="M98.4 180.5v.8M120.6 186.7v1.3h1.3l-1.3 1.2-1.2-1.2h1.2M146 186.7v1.3h1.3l-1.3 1.2-1.2-1.2h1.2M149.2 180.9h-1.3l.4 .4M149.2 180.5v.8"/>
</g>
<g fill="none" stroke="#0000c2" stroke-width=".33">
<path d="M194.8 25.1v3.1M234.4 25.1v3.1M45 41.7v3M45 54.4v3M45 69.6v3M45 82.3v3M74.7 98.6h3M32.8 177.3h3M41.7 177.3h3M68.3 178.3h3.1M93.7 178.3h3.1M102.6 177.3h3.1"/>
<path d="M119.1 177.3h3.1M144.5 178.3h3.1M153.4 177.3h3.1"/>
</g>
<g fill="none" stroke="#0000c2" stroke-width=".3">
<path d="M193.8 25.1v3.1M235.5 25.1v3.1M43.9 41.7v3M43.9 54.4v3M50.8 48.4h5.1v2.3h-5.1zM43.9 69.6v3M50.8 76.3h5.1v2.3h-5.1zM43.9 82.3v3M74.7 99.6h3M32.8 178.3h3M41.7 178.3h3M68.3 177.3h3.1"/>
<path d="M93.7 177.3h3.1M102.6 178.3h3.1M119.1 178.3h3.1M144.5 177.3h3.1M153.4 178.3h3.1"/>
</g>
<path d="M52.1 51.4h2.5M52.1 47.6h2.5M52.1 79.5h2.5M52.1 75.4h2.5" fill="none" stroke="#0000c2" stroke-width=".51"/>
<g fill="none" stroke="#848484" stroke-width=".18">
<path d="M191.8 26.7h-3.8v2.5M237.5 26.7h3.8v2.5M38.1 55.9h3.8M41.9 43.2h-3.8v15.2M38.1 77.5h10.2M41.9 71.1h-3.8v15.3M61 77.5v2.5M163.8 63.5h2.6v83.8M38.1 83.8h3.8M128.3 88.9h-2.6v58.4M76.2 101.6v3.8M125.7 106.7h2.6"/>
<path d="M163.8 106.7h2.6M125.7 139.7h2.6M34.3 180.3v3.9h35.5M43.2 180.3v3.9M52.1 180.3v3.9M61 180.3v3.9M69.8 180.3v6.4M95.2 180.3v6.4M104.1 180.3v3.9h-8.9M120.6 180.3v6.4M146 180.3v6.4M154.9 180.3v3.9h-8.9"/>
</g>
<g fill="none" stroke="#f90" stroke-width=".18">
<path d="M196.8 26.7h21.6v24.1M200.7 24.1v14M203.2 26.7v11.4M210.8 26.7v13.9M115.6 40.6v68.6h12.7M168.9 40.6v63.5h-5.1M163.8 61h5.1M123.2 109.2v33h5.1M43.2 171.5v3.8M52.1 171.5v3.8M61 171.5v3.8M69.8 168.9v6.4"/>
<path d="M80 171.5h-45.7v3.8"/>
</g>
<path d="M69.8 134.6v2.6h58.5M146 171.5h8.9v3.8M146 168.9v6.4" fill="none" stroke="#c080ff" stroke-width=".18"/>
<path d="M128.3 76.2h-40.7v16.5h-13.9M163.8 71.1h41.9M76.2 92.7v3.8M163.8 83.8h41.9M163.8 99.1h41.9M163.8 109.2h41.9" fill="none" stroke="#804d00" stroke-width=".18"/>
<path d="M120.6 45.7v45.7h7.7M85.1 171.5h19v3.8M95.2 168.9v6.4" fill="none" stroke="#ffc000" stroke-width=".18"/>
<path d="M125.7 50.8v10.2h2.6M120.6 168.9v6.4" fill="none" stroke="#dd8500" stroke-width=".18"/>
<path d="M203.2 45.7v22.9M203.2 58.4h10.2M205.7 48.3h-5v17.7M193 66h38.1M193 68.6h38.1" fill="none" stroke="#0080ff" stroke-width=".18"/>
<path d="M228.6 24.1v14M232.4 26.7h-6.3v11.4" fill="none" stroke="#f00" stroke-width=".18"/>
<path d="M215.9 48.3h15.2M223.5 58.4h7.6M226.1 45.7v12.7" fill="none" stroke="#0060c0" stroke-width=".18"/>
<path d="M163.8 116.8h41.9M163.8 111.8h41.9M163.8 114.3h41.9" fill="none" stroke="#008080" stroke-width=".18"/>
<path d="M163.8 94h64.8v38.1h2.5M163.8 137.2h67.3M193 139.7h38.1M193 134.6h38.1M193 142.2h38.1" fill="none" stroke="#004080" stroke-width=".18"/>
<g fill="none" stroke="#000084" stroke-width=".18">
<path d="M127.7 62.9l1.2 1.2M128.9 62.9l-1.2 1.2M163.2 78.1l1.2 1.2M164.4 78.1l-1.2 1.2M163.2 88.3l1.2 1.2M163.2 90.8l1.2 1.2M163.2 80.7l1.2 1.2M163.2 85.8l1.2 1.2M164.4 88.3l-1.2 1.2M164.4 90.8l-1.2 1.2M164.4 80.7l-1.2 1.2M164.4 85.8l-1.2 1.2"/>
<path d="M127.7 134l1.2 1.2M128.9 134l-1.2 1.2"/>
</g>
<g fill="#848484" stroke="#848484" stroke-width=".18">
<circle cx="52.1" cy="184.2" r=".46"/>
<circle cx="69.8" cy="184.2" r=".46"/>
<circle cx="43.2" cy="184.2" r=".46"/>
<circle cx="61" cy="184.2" r=".46"/>
<circle cx="38.1" cy="55.9" r=".46"/>
<circle cx="38.1" cy="77.5" r=".46"/>
<circle cx="38.1" cy="83.8" r=".46"/>
<circle cx="125.7" cy="139.7" r=".46"/>
<circle cx="95.2" cy="184.2" r=".46"/>
<circle cx="146" cy="184.2" r=".46"/>
<circle cx="166.4" cy="106.7" r=".46"/>
<circle cx="125.7" cy="106.7" r=".46"/>
</g>
<g fill="#f90" stroke="#f90" stroke-width=".18">
<circle cx="69.8" cy="171.5" r=".46"/>
<circle cx="43.2" cy="171.5" r=".46"/>
<circle cx="61" cy="171.5" r=".46"/>
<circle cx="52.1" cy="171.5" r=".46"/>
<circle cx="123.2" cy="109.2" r=".46"/>
<circle cx="168.9" cy="61" r=".46"/>
<circle cx="200.7" cy="26.7" r=".46"/>
<circle cx="210.8" cy="26.7" r=".46"/>
<circle cx="203.2" cy="26.7" r=".46"/>
</g>
<circle cx="76.2" cy="92.7" r=".46" fill="#804d00" stroke="#804d00" stroke-width=".18"/>
<circle cx="95.2" cy="171.5" r=".46" fill="#ffc000" stroke="#ffc000" stroke-width=".18"/>
<g fill="#000" stroke="#000" stroke-width=".18">
<circle cx="53.3" cy="43.2" r=".46"/>
<circle cx="53.3" cy="55.9" r=".46"/>
<circle cx="53.3" cy="71.1" r=".46"/>
<circle cx="53.3" cy="83.8" r=".46"/>
</g>
<circle cx="146" cy="171.5" r=".46" fill="#c080ff" stroke="#c080ff" stroke-width=".18"/>
<g fill="#0080ff" stroke="#0080ff" stroke-width=".18">
<circle cx="203.2" cy="68.6" r=".46"/>
<circle cx="200.7" cy="66" r=".46"/>
<circle cx="200.7" cy="48.3" r=".46"/>
<circle cx="203.2" cy="58.4" r=".46"/>
</g>
<g fill="#0060c0" stroke="#0060c0" stroke-width=".18">
<circle cx="228.6" cy="48.3" r=".46"/>
<circle cx="226.1" cy="58.4" r=".46"/>
</g>
<circle cx="228.6" cy="26.7" r=".46" fill="#f00" stroke="#f00" stroke-width=".18"/>
<use href="#words"/>
</svg>
